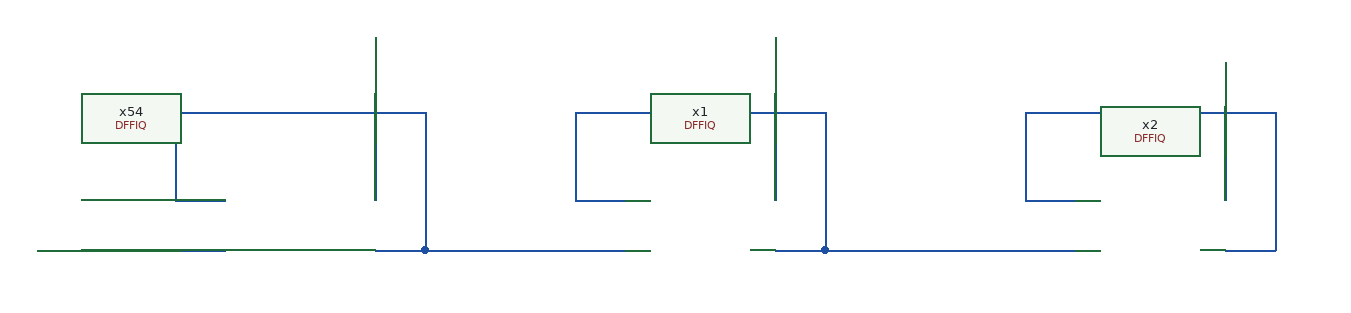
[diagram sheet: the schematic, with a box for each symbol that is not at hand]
v {xschem version=3.4.5 file_version=1.2
}
G {}
K {}
V {}
S {}
E {}
N 140 -390 180 -390 {
lab=#net1}
N 140 -460 140 -390 {
lab=#net1}
N 140 -460 340 -460 {
lab=#net1}
N 340 -460 340 -350 {
lab=#net1}
N 300 -350 340 -350 {
lab=#net1}
N 460 -390 500 -390 {
lab=#net2}
N 460 -460 460 -390 {
lab=#net2}
N 460 -460 660 -460 {
lab=#net2}
N 660 -460 660 -350 {
lab=#net2}
N 620 -350 660 -350 {
lab=#net2}
N 820 -390 860 -390 {
lab=#net3}
N 820 -460 820 -390 {
lab=#net3}
N 820 -460 1020 -460 {
lab=#net3}
N 1020 -460 1020 -350 {
lab=#net3}
N 980 -350 1020 -350 {
lab=#net3}
N 340 -350 500 -350 {
lab=#net1}
N 660 -350 860 -350 {
lab=#net2}
N 300 -520 300 -390 {
lab=#net4}
N 620 -520 620 -390 {
lab=#net5}
N 980 -500 980 -390 {
lab=#net6}
N 30 -350 180 -350 {
lab=#net7}
C {stdcells/DFFIQ.sym} 240 -370 0 0 {name=x54 VCCPIN=VCC VSSPIN=VSS VCCBPIN=VCC VSSBPIN=VSS}
C {stdcells/DFFIQ.sym} 560 -370 0 0 {name=x1 VCCPIN=VCC VSSPIN=VSS VCCBPIN=VCC VSSBPIN=VSS}
C {stdcells/DFFIQ.sym} 920 -370 0 0 {name=x2 VCCPIN=VCC VSSPIN=VSS VCCBPIN=VCC VSSBPIN=VSS}
